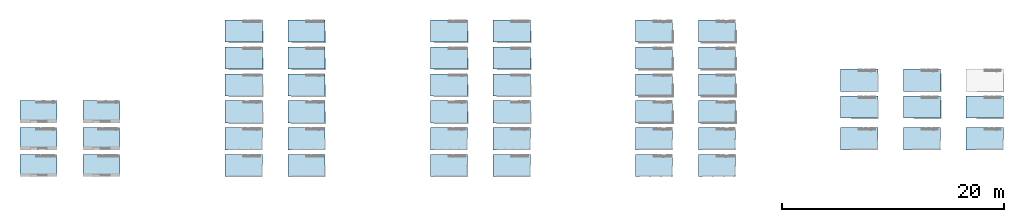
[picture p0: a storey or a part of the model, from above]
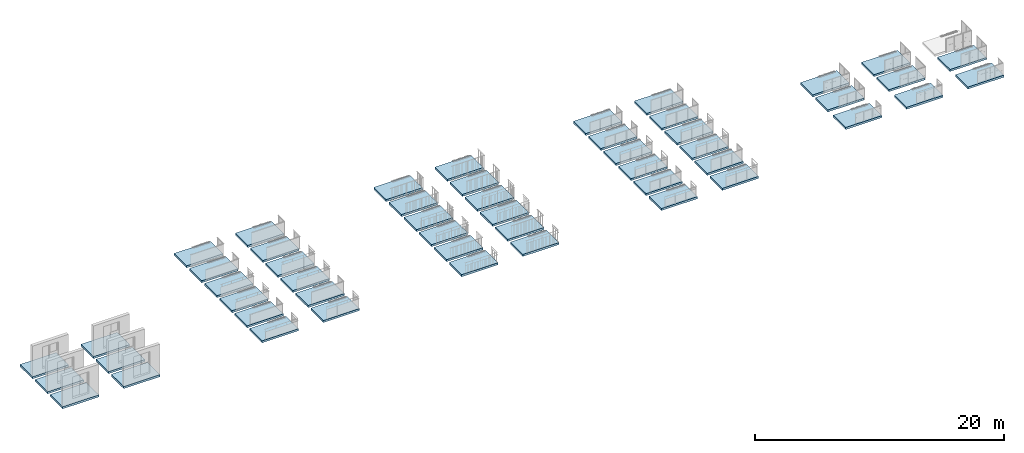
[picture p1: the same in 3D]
Properties of the parts of a building model (IFC2X3)

# File
Description: ViewDefinition [CoordinationView_V2.0], Option [Drawing Scale: 100.000000], Option [Global Unique Identifiers (GUID): Keep existing], Option [Elements to export: Visible elements (on all stories)], Option [Partial Structure Display: Entire Model], Option [IFC Domain: All], Option [Structural Function: All Elements], Option [Convert Grid elements: On], Option [Convert IFC Annotations and ARCHICAD 2D elements: Off], Option [Convert 2D symbols of Doors and Windows: Off], Option [Explode Composite and Complex Profile elements into parts: Off], Option [Export geometries that Participates in Collision Detection only: Off], Option [Multi-skin complex geometries: Building element parts], Option [Elements in Solid Element Operations: Extruded/revolved], Option [Elements with junctions: Extruded/revolved without junctions], Option [Slabs with slanted edge(s): Extruded], Option [Use legacy geometric methods as in Coordination View 1.0: Off], Option [IFC Site Geometry: As boundary representation (BRep)], Option [IFC Site Location: At Project Origin], Option [Curtain Wall export mode: Container Element], Option [Railing export mode: Single Element], Option [Stair export mode: Container Element], Option [Properties To Export: All properties], Option [Space containment: Off], Option [Bounding Box: Off], Option [Geometry to type objects: Off], Option [Element Properties: All], Option [Building Material Properties: Off], Option [Element Parameters: Off], Option [Component Parameters: Off], Option [IFC Base Quantities: Off], Option [Door Window Parameters: On], Option [IFC Space boundaries: Off], Option [ARCHICAD Zone Categories as IFC Space classification data: Off], Option [Element Classifications: On]
File name: C:\Users\RahiL\Downloads\Innore OÜ Railings.ifc
Time: 2019-06-12T11:39:00
Author: Architect
Organization: Building Designer Office
Written by: The EXPRESS Data Manager Version 5.02.0100.09 : 26 Sep 2013
Made in: IFC file generated by GRAPHISOFT ARCHICAD-64 22.0.0 INT FULL Windows version (IFC add-on version: 4023 INT FULL).
Authorization: The authorising person

# IfcSite, Site
RefLatitude: 47, 33, 34, 948800; RefLongitude: 19, 3, 17, 204400; RefElevation: 0 mm

# IfcBuildingStorey, Ground Floor
In: Building
Elevation: 0 mm

# IfcDiscreteAccessory: Text 3D 22 (51)
In: Ground Floor
Classification: Discrete Accessory (ARCHICAD Classification)
MANUFACTURING - Manufacturer: Innore OÜ; Product Website: www.innore.eu
PRODUCT DESCRIPTION (Expression) - Dynamic ID by Classification: Discrete Accessory - 001
AC_Pset_RenovationAndPhasing - Renovation Status: Existing

# IfcRailing: Railing Type (51)
In: Ground Floor
Classification: Railing (ARCHICAD Classification)
Developer - Developer: TuLiTec OÜ
Pset_ManufacturerTypeInformation - Manufacturer: INNORE OÜ
MANUFACTURING - Manufacturer: INNORE OÜ; Product Website: http://www.innore.eu/en
AC_Pset_RenovationAndPhasing - Renovation Status: Existing
Name | Material | ModelLabel = Model | Dynamic ID by Classification
G-Line BERGEN 1,0m T1 | Aluminium (14), Glass (4) | G-Line BERGEN 1,0m T1 | Railing -Line BERGEN 1,0m T1
G-Line BERGEN 1,0m T3 | Aluminium (14), Glass (4) | G-Line BERGEN 1,0m T3 | Railing -Line BERGEN 1,0m T3
G-Line BERGEN 1,0m S1 | Aluminium (8), Glass (4) | G-Line BERGEN 1,0m S1 | Railing -Line BERGEN 1,0m S1
G-Line BERGEN 1,0m S2 | Aluminium (8), Glass (4) | G-Line BERGEN 1,0m S2 | Railing -Line BERGEN 1,0m S2
G-Line BERGEN 1,0m S3 | Aluminium (8), Glass (4) | G-Line BERGEN 1,0m S3 | Railing -Line BERGEN 1,0m S3
G-Line BERGEN 1,0m S4 | Aluminium (8), Glass (4) | G-Line BERGEN 1,0m S4 | Railing -Line BERGEN 1,0m S4
G-Line BERGEN 1,2m T1 | Aluminium (14), Glass (4) | G-Line BERGEN 1,2m T1 | Railing -Line BERGEN 1,2m T1
G-Line BERGEN 1,2m T3 | Aluminium (14), Glass (4) | G-Line BERGEN 1,2m T3 | Railing -Line BERGEN 1,2m T3
G-Line BERGEN 1,2m S1 | Aluminium (8), Glass (4) | G-Line BERGEN 1,2m S1 | Railing -Line BERGEN 1,2m S1
G-Line BERGEN 1,2m S2 | Aluminium (8), Glass (4) | G-Line BERGEN 1,2m S2 | Railing -Line BERGEN 1,2m S2
G-Line BERGEN 1,2m S3 | Aluminium (8), Glass (4) | G-Line BERGEN 1,2m S3 | Railing -Line BERGEN 1,2m S3
G-Line BERGEN 1,2m S4 | Aluminium (8), Glass (4) | G-Line BERGEN 1,2m S4 | Railing -Line BERGEN 1,2m S4
2 x A-Line BODO 1,0m T3 | Aluminium (54) | A-Line BODO 1,0m T3 | Railing -Line BODO 1,0m T3
A-Line BODO 1,0m S1 | Aluminium (54) | A-Line BODO 1,0m S1 | Railing -Line BODO 1,0m S1
A-Line BODO 1,0m S2 | Aluminium (58) | A-Line BODO 1,0m S2 | Railing -Line BODO 1,0m S2
A-Line BODO 1,0m S3 | Aluminium (58) | A-Line BODO 1,0m S3 | Railing -Line BODO 1,0m S3
A-Line BODO 1,0m S4 | Aluminium (58) | A-Line BODO 1,0m S4 | Railing -Line BODO 1,0m S4
A-Line BODO 1,2m T1 | Aluminium (54) | A-Line BODO 1,2m T1 | Railing -Line BODO 1,2m T1
A-Line BODO 1,2m T3 | Aluminium (54) | A-Line BODO 1,2m T3 | Railing -Line BODO 1,2m T3
A-Line BODO 1,2m S1 | Aluminium (54) | A-Line BODO 1,2m S1 | Railing -Line BODO 1,2m S1
A-Line BODO 1,2m S2 | Aluminium (58) | A-Line BODO 1,2m S2 | Railing -Line BODO 1,2m S2
A-Line BODO 1,2m S3 | Aluminium (58) | A-Line BODO 1,2m S3 | Railing -Line BODO 1,2m S3
A-Line BODO 1,2m S4 | Aluminium (58) | A-Line BODO 1,2m S4 | Railing -Line BODO 1,2m S4
G-Line OSLO 1,0m T1 | Aluminium (22), Glass (4) | G-Line OSLO 1,0m T1 | Railing -Line OSLO 1,0m T1
G-Line OSLO 1,0m T3 | Aluminium (22), Glass (4) | G-Line OSLO 1,0m T3 | Railing -Line OSLO 1,0m T3
G-Line OSLO 1,0m S1 | Aluminium (12), Glass (4) | G-Line OSLO 1,0m S1 | Railing -Line OSLO 1,0m S1
G-Line OSLO 1,0m S2 | Aluminium (12), Glass (4) | G-Line OSLO 1,0m S2 | Railing -Line OSLO 1,0m S2
G-Line OSLO 1,0m S3 | Aluminium (12), Glass (4) | G-Line OSLO 1,0m S3 | Railing -Line OSLO 1,0m S3
G-Line OSLO 1,0m S4 | Aluminium (12), Glass (4) | G-Line OSLO 1,0m S4 | Railing -Line OSLO 1,0m S4
G-Line OSLO 1,2m T1 | Aluminium (18), Glass (4) | G-Line OSLO 1,2m T1 | Railing -Line OSLO 1,2m T1
G-Line OSLO 1,2m T3 | Aluminium (18), Glass (4) | G-Line OSLO 1,2m T3 | Railing -Line OSLO 1,2m T3
G-Line OSLO 1,2m S1 | Aluminium (12), Glass (4) | G-Line OSLO 1,2m S1 | Railing -Line OSLO 1,2m S1
G-Line OSLO 1,2m S2 | Aluminium (12), Glass (4) | G-Line OSLO 1,2m S2 | Railing -Line OSLO 1,2m S2
G-Line OSLO 1,2m S3 | Aluminium (12), Glass (4) | G-Line OSLO 1,2m S4 | Railing -Line OSLO 1,2m S3
G-Line OSLO 1,2m S4 | Aluminium (12), Glass (4) | G-Line OSLO 1,2m S4 | Railing -Line OSLO 1,2m S4
2 x F-Line GOTLAND 1,1m | Steel - Structural (2), Aluminium (5) | G-Line GOTLAND 1,1m | Railing -Line GOTLAND 1,1m
F-Line NORDKAPP 1,0m | Aluminium (6) | G-Line NORDKAPP 1,0m | Railing -Line NORDKAPP 1,0m
F-Line NORDKAPP 1,1m | Aluminium (6) | G-Line NORDKAPP 1,1m | Railing -Line NORDKAPP 1,1m
F-Line NORDKAPP 1,2m | Aluminium (6) | G-Line NORDKAPP 1,2m | Railing -Line NORDKAPP 1,2m
F-Line GOTLAND 1,0m | Steel - Structural (2), Aluminium (5) | G-Line GOTLAND 1,0m | Railing -Line GOTLAND 1,0m
E-Line SOLAR 1,0m T3 | Aluminium (14), GENERIC - EXTERNAL CLADDING (84) | G-Line BERGEN 1,0m T3 | Railing -Line SOLAR 1,0m T3
E-Line SOLAR 1,2m T3 | Aluminium (14), GENERIC - EXTERNAL CLADDING (84) | G-Line BERGEN 1,2m T3 | Railing -Line SOLAR 1,2m T3
E-Line SOLAR 1,0m S4 | Aluminium (10), GENERIC - EXTERNAL CLADDING (145) | G-Line BERGEN 1,0m S4 | Railing -Line SOLAR 1,0m S4
E-Line SOLAR 1,2m S4 | Aluminium (10), GENERIC - EXTERNAL CLADDING (145) | G-Line BERGEN 1,2m S4 | Railing -Line SOLAR 1,2m S4
E-Line SOLAR 1,2m S3 | Aluminium (10), GENERIC - EXTERNAL CLADDING (125) | G-Line BERGEN 1,2m S3 | Railing -Line SOLAR 1,2m S3
E-Line SOLAR 1,0m S3 | Aluminium (10), GENERIC - EXTERNAL CLADDING (105) | G-Line BERGEN 1,0m S3 | Railing -Line SOLAR 1,0m S3
E-Line SOLAR 1,2m T3 | Aluminium (14), GENERIC - EXTERNAL CLADDING (100) | G-Line BERGEN 1,2m T3 | Railing -Line SOLAR 1,2m T3
E-Line SOLAR 1,2m S3 | Aluminium (10), GENERIC - EXTERNAL CLADDING (145) | G-Line BERGEN 1,2m S3 | Railing -Line SOLAR 1,2m S3
E-Line SOLAR 1,2m S4 | Aluminium (10), GENERIC - EXTERNAL CLADDING (165) | G-Line BERGEN 1,2m S4 | Railing -Line SOLAR 1,2m S4

# IfcSlab: GENERIC - EXTERNAL CLADDING 200 (51)
In: Ground Floor
Type - PredefinedType: FLOOR
Classification: Slab (ARCHICAD Classification); Material: GENERIC - EXTERNAL CLADDING 200 mm
NUMBER OF FLOOR TILES (Expression) - Number of tiles [not rounded]: 159.682; Number of tiles [round up]: 160; Number of cut tiles: 1; Tile Dimension 1: 200 mm; Tile Dimension 2: 200 mm; Grouting Width: 5 mm
COST OF STRUCTURE (Expression) - Cost Per Volume: 45; Total Cost of Volume (USD): 60.40 USD; Total Cost of Volume ($): 60.40 $
PRODUCT DESCRIPTION (Expression) - Dynamic ID by Classification: Slab - 001
GENERAL SURFACE DATA (Mapping) - Top Surface (General): Paint - Titanium White; Edge Surface (General): Paint - Titanium White; Bottom Surface (General): Paint - Titanium White; Top Surface Area (General): 6.71065 m2; Conditional Surface Area of the Top (General): 6.71065 m2; Edge Surface Area (General): 2.14213 m2; Bottom Surface Area (General): 6.71065 m2; Conditional Surface Area of the Bottom (General): 6.71065 m2
AC_Pset_RenovationAndPhasing - Renovation Status: Existing

# IfcWallStandardCase: GENERIC - STRUCTURAL 300 (6)
In: Ground Floor
Classification: Wall (ARCHICAD Classification); Material: GENERIC - STRUCTURAL 300 mm
NUMBER OF BRICKS (Expression) - Brick type and measures: Standard - 92 mm × 57 mm × 203 mm; No. of bricks to purchase: 1426; Brick H size: 92 mm; Brick W size: 57 mm; Brick L size: 203 mm; Mortar thickness: 10 mm; Brick volume: 0.00145564 m3
SUSPENDED CEILING LEVEL (Expression) - Interior height detailed: 2.50below suspended celing, up to0.30 under structural slab; Sub Ceiling thickness: 300 mm; Sub Floor Thickness: 200 mm; Suspended Ceiling level: 2700 mm; Raised Floor Level: 200 mm; Interior height: 2500 mm
COST OF STRUCTURE (Expression) - Cost Per Volume: 45; Total Cost of Volume: 135.891; Total Cost of Volume (USD): 135.89 USD; Total Cost of Volume ($): 135.89 $
PRODUCT DESCRIPTION (Expression) - Dynamic ID by Classification: Wall - 002
GENERAL SURFACE DATA (Mapping) - Edge Surface (General): Paint - Titanium White; Top Surface Area (General): 1.0066 m2; Edge Surface Area (General): 3.81319 m2; Bottom Surface Area (General): 1.0066 m2
AC_Pset_RenovationAndPhasing - Renovation Status: Existing
NUMBER OF FLOOR TILES (Expression) - Tile Dimension 1: 200 mm; Tile Dimension 2: 200 mm; Grouting Width: 5 mm

# IfcWindow: Double Window 22 (6)
In: Ground Floor
Type - OperationType: DOUBLE_PANEL_VERTICAL; ParameterTakesPrecedence: no; Sizeable: no
Type - Window Lining Properties - LiningDepth: 50 mm; LiningThickness: 50 mm; MullionThickness: 50 mm; FirstMullionOffset: 0.483333
Type - Window Panel Properties - Panel 1 - OperationType: FIXEDCASEMENT; PanelPosition: LEFT
Type - Window Panel Properties - Panel 2 - OperationType: SIDEHUNGLEFTHAND; PanelPosition: RIGHT; FrameDepth: 50 mm; FrameThickness: 50 mm
OverallHeight: 2100 mm; OverallWidth: 1500 mm; Classification: Window (ARCHICAD Classification)
Pset_WindowCommon - ThermalTransmittance: 0; GlazingAreaFraction: 2.46875
MANUFACTURING - Manufacturer: Innore OÜ; Product Website: www.innore.eu
PRODUCT DESCRIPTION (Expression) - Dynamic ID by Classification: Window - 002; Hotlinked Door Context ID: 002; Stair Subelements - Numerical IDs: 002
AC_Pset_RenovationAndPhasing - Renovation Status: Existing
